One B-rep face of a CAD part: STEP entity #170.
In plain terms, the planar face has unit normal (1, 0, 0).
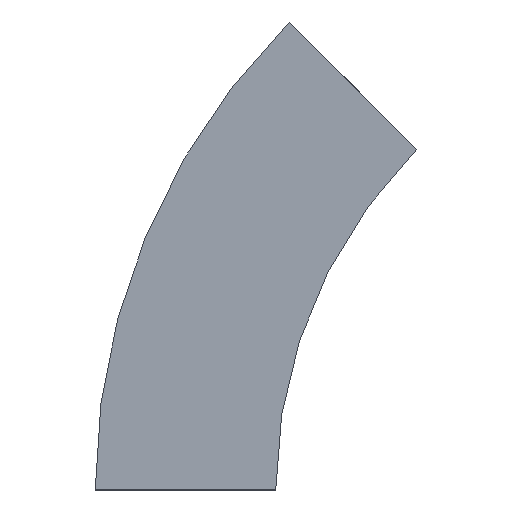
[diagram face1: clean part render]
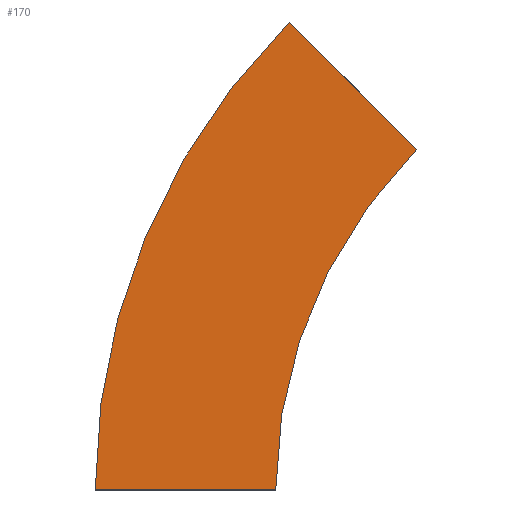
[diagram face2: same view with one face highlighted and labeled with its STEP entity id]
Its self-contained STEP definition (entity closure, numbers rounded to 3 decimals):
#5 = DIRECTION ( 'NONE',  ( 0., 0.707, 0.707 ) ) ;
#15 = VERTEX_POINT ( 'NONE', #485 ) ;
#23 = ORIENTED_EDGE ( 'NONE', *, *, #556, .F. ) ;
#58 = CARTESIAN_POINT ( 'NONE',  ( 0., 112.5, 0. ) ) ;
#61 = VERTEX_POINT ( 'NONE', #58 ) ;
#117 = DIRECTION ( 'NONE',  ( 1., 0., 0. ) ) ;
#118 = FACE_OUTER_BOUND ( 'NONE', #281, .T. ) ;
#125 = VECTOR ( 'NONE', #5, 1000. ) ;
#146 = CIRCLE ( 'NONE', #529, 412.5 ) ;
#165 = CARTESIAN_POINT ( 'NONE',  ( 0., 0., 0. ) ) ;
#170 = ADVANCED_FACE ( 'NONE', ( #118 ), #247, .T. ) ;
#176 = LINE ( 'NONE', #417, #228 ) ;
#211 = CIRCLE ( 'NONE', #265, 300. ) ;
#214 = EDGE_CURVE ( 'NONE', #437, #61, #176, .T. ) ;
#228 = VECTOR ( 'NONE', #367, 1000. ) ;
#240 = ORIENTED_EDGE ( 'NONE', *, *, #552, .T. ) ;
#247 = PLANE ( 'NONE',  #275 ) ;
#252 = DIRECTION ( 'NONE',  ( 0., 0., -1. ) ) ;
#265 = AXIS2_PLACEMENT_3D ( 'NONE', #497, #117, #315 ) ;
#275 = AXIS2_PLACEMENT_3D ( 'NONE', #165, #455, #252 ) ;
#281 = EDGE_LOOP ( 'NONE', ( #240, #23, #415, #326 ) ) ;
#296 = EDGE_CURVE ( 'NONE', #437, #490, #211, .T. ) ;
#304 = LINE ( 'NONE', #397, #125 ) ;
#313 = DIRECTION ( 'NONE',  ( 0., 1., 0. ) ) ;
#315 = DIRECTION ( 'NONE',  ( 0., 1., 0. ) ) ;
#326 = ORIENTED_EDGE ( 'NONE', *, *, #214, .T. ) ;
#367 = DIRECTION ( 'NONE',  ( 0., 1., 0. ) ) ;
#395 = DIRECTION ( 'NONE',  ( 1., 0., 0. ) ) ;
#397 = CARTESIAN_POINT ( 'NONE',  ( 0., -87.868, 212.132 ) ) ;
#414 = CARTESIAN_POINT ( 'NONE',  ( 0., 0., 0. ) ) ;
#415 = ORIENTED_EDGE ( 'NONE', *, *, #296, .F. ) ;
#417 = CARTESIAN_POINT ( 'NONE',  ( 0., 0., 0. ) ) ;
#437 = VERTEX_POINT ( 'NONE', #414 ) ;
#455 = DIRECTION ( 'NONE',  ( 1., 0., 0. ) ) ;
#485 = CARTESIAN_POINT ( 'NONE',  ( 0., -8.318, 291.682 ) ) ;
#490 = VERTEX_POINT ( 'NONE', #548 ) ;
#497 = CARTESIAN_POINT ( 'NONE',  ( 0., -300., 0. ) ) ;
#524 = CARTESIAN_POINT ( 'NONE',  ( 0., -300., 0. ) ) ;
#529 = AXIS2_PLACEMENT_3D ( 'NONE', #524, #395, #313 ) ;
#548 = CARTESIAN_POINT ( 'NONE',  ( 0., -87.868, 212.132 ) ) ;
#552 = EDGE_CURVE ( 'NONE', #61, #15, #146, .T. ) ;
#556 = EDGE_CURVE ( 'NONE', #490, #15, #304, .T. ) ;
